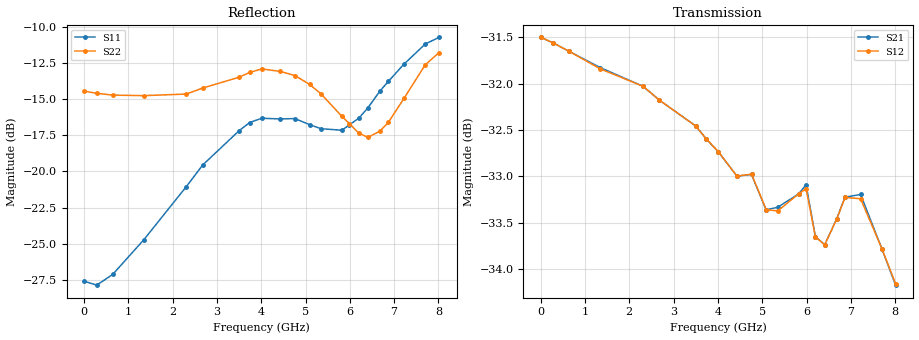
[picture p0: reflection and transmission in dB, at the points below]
! DEVICE ID: PE43712
! File Path: z:\PE43713\PE43713_CHAR_NOM_04292014\AMB\3p300\LS_ATT_30p25dB\PE43713_AMB_3p300V_3p000V_0p000V_LS_ATT_30p25dB_S2P_SN_10_A0139A.s2p
! Serial: 10
! Lot: A0139A
! Temp: 25C
! VDD: 3.300
! VSS: 0.000
! Control_Hi: 3.000
! Control_Lo: 0.000
! Attenuation Step: 30.25dB
! Port 1: RF1
! Port 2: RF2
! ThroughPath:1-2
! IDD: 0.0001456936
! ISS: -1.719e-007
#  Hz  S  RI  R  50
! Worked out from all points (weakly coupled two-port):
!   801 points, 10 MHz to 8.01 GHz, reference 50 ohm
!   highest |S21| = -31.51 dB at 10 MHz (marker M1); lowest = -34.2 dB at 8.01 GHz (marker M2)
!   lowest |S11| = -27.9 dB at 290 MHz (marker M3), VSWR 1.08, Z = 46.3 + j1.23 ohm
!   |S11| at or under -10 dB: start of sweep to end of sweep
!   |S22| runs from -17.6 to -11.8 dB; largest |S21 - S12| = 0.00011
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1e7  -0.0416 0.000899  0.0266 -0.000126  0.0266 -0.000125  -0.1899 0.00128
2.9e8  -0.0381 0.0133  0.0263 -0.00246  0.0263 -0.00245  -0.1857 0.0195
6.5e8  -0.0338 0.0281  0.0256 -0.00528  0.0256 -0.00528  -0.1793 0.0415
1.35e9  -0.021 0.054  0.0235 -0.0102  0.0235 -0.0101  -0.1643 0.0812
2.31e9  0.0103 0.088  0.0195 -0.0157  0.0195 -0.0157  -0.1282 0.1342
2.68e9  0.025 0.1023  0.0175 -0.0173  0.0175 -0.0173  -0.1115 0.1596
3.5e9  0.0484 0.1297  0.0128 -0.0201  0.0128 -0.0201  -0.0858 0.1942
3.74e9  0.0533 0.1379  0.0112 -0.0206  0.0112 -0.0206  -0.0828 0.2044
4.01e9  0.0582 0.1415  0.00957 -0.021  0.00958 -0.021  -0.081 0.2119
4.43e9  0.0636 0.1382  0.00721 -0.0212  0.00721 -0.0212  -0.0706 0.2109
4.76e9  0.0721 0.1345  0.00531 -0.0218  0.00535 -0.0218  -0.0644 0.2053
5.09e9  0.082 0.1201  0.0034 -0.0212  0.00344 -0.0212  -0.0553 0.1928
5.35e9  0.0911 0.1073  0.00248 -0.0214  0.00249 -0.0213  -0.047 0.1798
5.82e9  0.1143 0.0791  -2.88e-05 -0.0219  2.16e-05 -0.0219  -0.0133 0.1548
5.99e9  0.1269 0.0704  -0.00147 -0.0221  -0.00143 -0.022  0.00277 0.1466
6.2e9  0.1414 0.0584  -0.00267 -0.0206  -0.00263 -0.0206  0.0257 0.1334
6.41e9  0.1583 0.0514  -0.00259 -0.0204  -0.00256 -0.0204  0.0503 0.1213
6.68e9  0.1852 0.0435  -0.00373 -0.0209  -0.00372 -0.0209  0.0838 0.1097
6.87e9  0.2017 0.039  -0.00514 -0.0212  -0.00511 -0.0212  0.1039 0.1056
7.22e9  0.2329 0.0354  -0.00793 -0.0204  -0.00787 -0.0203  0.1445 0.1059
7.7e9  0.2739 0.0391  -0.00973 -0.018  -0.00974 -0.018  0.2024 0.1181
8.01e9  0.2886 0.0433  -0.0105 -0.0165  -0.0104 -0.0166  0.2263 0.1246
